VERSION 5.8 ;
BUSBITCHARS "[]" ;
DIVIDERCHAR "/" ;
UNITS
    DATABASE MICRONS 2000 ;
END UNITS

VIA PLL_COUNTER_DCO_PHYS_via1_2_2240_1200_1_2_1040_1040
  VIARULE Via1_GEN_HH ;
  CUTSIZE 0.26 0.26 ;
  LAYERS Metal1 Via1 Metal2 ;
  CUTSPACING 0.26 0.26 ;
  ENCLOSURE 0.06 0.17 0.01 0.06 ;
  ROWCOL 1 2 ;
END PLL_COUNTER_DCO_PHYS_via1_2_2240_1200_1_2_1040_1040

VIA PLL_COUNTER_DCO_PHYS_via2_3_2240_1200_1_2_1040_1040
  VIARULE Via2_GEN_HH ;
  CUTSIZE 0.26 0.26 ;
  LAYERS Metal2 Via2 Metal3 ;
  CUTSPACING 0.26 0.26 ;
  ENCLOSURE 0.01 0.06 0.06 0.01 ;
  ROWCOL 1 2 ;
END PLL_COUNTER_DCO_PHYS_via2_3_2240_1200_1_2_1040_1040

VIA PLL_COUNTER_DCO_PHYS_via3_4_2240_1200_1_2_1040_1040
  VIARULE Via3_GEN_HH ;
  CUTSIZE 0.26 0.26 ;
  LAYERS Metal3 Via3 Metal4 ;
  CUTSPACING 0.26 0.26 ;
  ENCLOSURE 0.06 0.01 0.17 0.06 ;
  ROWCOL 1 2 ;
END PLL_COUNTER_DCO_PHYS_via3_4_2240_1200_1_2_1040_1040

VIA PLL_COUNTER_DCO_PHYS_via4_5_2240_1800_2_2_1040_1040
  VIARULE Via4_GEN_HH ;
  CUTSIZE 0.26 0.26 ;
  LAYERS Metal4 Via4 Metal5 ;
  CUTSPACING 0.26 0.26 ;
  ENCLOSURE 0.17 0.06 0.06 0.06 ;
  ROWCOL 2 2 ;
END PLL_COUNTER_DCO_PHYS_via4_5_2240_1800_2_2_1040_1040

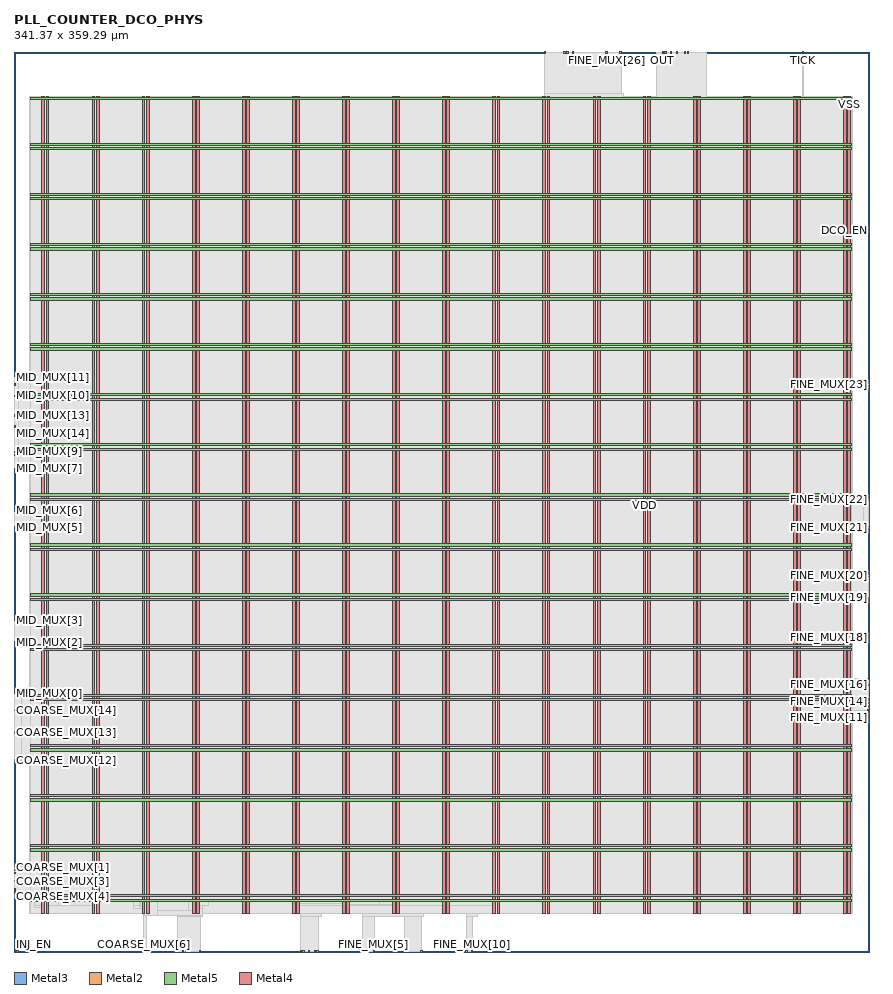
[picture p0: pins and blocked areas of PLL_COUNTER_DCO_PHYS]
MACRO PLL_COUNTER_DCO_PHYS
  FOREIGN PLL_COUNTER_DCO_PHYS 0 0 ;
  CLASS BLOCK ;
  SIZE 341.37 BY 359.29 ;
  PIN COARSE_MUX[0]
    DIRECTION INPUT ;
    USE SIGNAL ;
    PORT
      LAYER Metal3 ;
        RECT  0 32.48 0.56 33.04 ;
    END
  END COARSE_MUX[0]
  PIN COARSE_MUX[10]
    DIRECTION INPUT ;
    USE SIGNAL ;
    PORT
      LAYER Metal2 ;
        RECT  73.92 0 74.48 0.56 ;
    END
  END COARSE_MUX[10]
  PIN COARSE_MUX[11]
    DIRECTION INPUT ;
    USE SIGNAL ;
    PORT
      LAYER Metal2 ;
        RECT  64.96 0 65.52 0.56 ;
    END
  END COARSE_MUX[11]
  PIN COARSE_MUX[12]
    DIRECTION INPUT ;
    USE SIGNAL ;
    PORT
      LAYER Metal3 ;
        RECT  0 76.16 0.56 76.72 ;
    END
  END COARSE_MUX[12]
  PIN COARSE_MUX[13]
    DIRECTION INPUT ;
    USE SIGNAL ;
    PORT
      LAYER Metal3 ;
        RECT  0 87.36 0.56 87.92 ;
    END
  END COARSE_MUX[13]
  PIN COARSE_MUX[14]
    DIRECTION INPUT ;
    USE SIGNAL ;
    PORT
      LAYER Metal3 ;
        RECT  0 96.32 0.56 96.88 ;
    END
  END COARSE_MUX[14]
  PIN COARSE_MUX[1]
    DIRECTION INPUT ;
    USE SIGNAL ;
    PORT
      LAYER Metal3 ;
        RECT  0 33.6 0.56 34.16 ;
    END
  END COARSE_MUX[1]
  PIN COARSE_MUX[2]
    DIRECTION INPUT ;
    USE SIGNAL ;
    PORT
      LAYER Metal3 ;
        RECT  0 31.36 0.56 31.92 ;
    END
  END COARSE_MUX[2]
  PIN COARSE_MUX[3]
    DIRECTION INPUT ;
    USE SIGNAL ;
    PORT
      LAYER Metal3 ;
        RECT  0 28 0.56 28.56 ;
    END
  END COARSE_MUX[3]
  PIN COARSE_MUX[4]
    DIRECTION INPUT ;
    USE SIGNAL ;
    PORT
      LAYER Metal3 ;
        RECT  0 24.64 0.56 25.2 ;
    END
  END COARSE_MUX[4]
  PIN COARSE_MUX[5]
    DIRECTION INPUT ;
    USE SIGNAL ;
    PORT
      LAYER Metal3 ;
        RECT  0 23.52 0.56 24.08 ;
    END
  END COARSE_MUX[5]
  PIN COARSE_MUX[6]
    DIRECTION INPUT ;
    USE SIGNAL ;
    PORT
      LAYER Metal2 ;
        RECT  51.52 0 52.08 0.56 ;
    END
  END COARSE_MUX[6]
  PIN COARSE_MUX[7]
    DIRECTION INPUT ;
    USE SIGNAL ;
    PORT
      LAYER Metal2 ;
        RECT  52.64 0 53.2 0.56 ;
    END
  END COARSE_MUX[7]
  PIN COARSE_MUX[8]
    DIRECTION INPUT ;
    USE SIGNAL ;
    PORT
      LAYER Metal2 ;
        RECT  67.2 0 67.76 0.56 ;
    END
  END COARSE_MUX[8]
  PIN COARSE_MUX[9]
    DIRECTION INPUT ;
    USE SIGNAL ;
    PORT
      LAYER Metal2 ;
        RECT  68.32 0 68.88 0.56 ;
    END
  END COARSE_MUX[9]
  PIN DCO_EN
    DIRECTION INPUT ;
    USE SIGNAL ;
    PORT
      LAYER Metal3 ;
        RECT  340.81 287.84 341.37 288.4 ;
    END
  END DCO_EN
  PIN FINE_MUX[0]
    DIRECTION INPUT ;
    USE SIGNAL ;
    PORT
      LAYER Metal2 ;
        RECT  114.24 0 114.8 0.56 ;
    END
  END FINE_MUX[0]
  PIN FINE_MUX[10]
    DIRECTION INPUT ;
    USE SIGNAL ;
    PORT
      LAYER Metal2 ;
        RECT  182.56 0 183.12 0.56 ;
    END
  END FINE_MUX[10]
  PIN FINE_MUX[11]
    DIRECTION INPUT ;
    USE SIGNAL ;
    PORT
      LAYER Metal3 ;
        RECT  340.81 96.32 341.37 96.88 ;
    END
  END FINE_MUX[11]
  PIN FINE_MUX[12]
    DIRECTION INPUT ;
    USE SIGNAL ;
    PORT
      LAYER Metal3 ;
        RECT  340.81 97.44 341.37 98 ;
    END
  END FINE_MUX[12]
  PIN FINE_MUX[13]
    DIRECTION INPUT ;
    USE SIGNAL ;
    PORT
      LAYER Metal3 ;
        RECT  340.81 98.56 341.37 99.12 ;
    END
  END FINE_MUX[13]
  PIN FINE_MUX[14]
    DIRECTION INPUT ;
    USE SIGNAL ;
    PORT
      LAYER Metal3 ;
        RECT  340.81 99.68 341.37 100.24 ;
    END
  END FINE_MUX[14]
  PIN FINE_MUX[15]
    DIRECTION INPUT ;
    USE SIGNAL ;
    PORT
      LAYER Metal3 ;
        RECT  340.81 100.8 341.37 101.36 ;
    END
  END FINE_MUX[15]
  PIN FINE_MUX[16]
    DIRECTION INPUT ;
    USE SIGNAL ;
    PORT
      LAYER Metal3 ;
        RECT  340.81 106.4 341.37 106.96 ;
    END
  END FINE_MUX[16]
  PIN FINE_MUX[17]
    DIRECTION INPUT ;
    USE SIGNAL ;
    PORT
      LAYER Metal3 ;
        RECT  340.81 108.64 341.37 109.2 ;
    END
  END FINE_MUX[17]
  PIN FINE_MUX[18]
    DIRECTION INPUT ;
    USE SIGNAL ;
    PORT
      LAYER Metal3 ;
        RECT  340.81 125.44 341.37 126 ;
    END
  END FINE_MUX[18]
  PIN FINE_MUX[19]
    DIRECTION INPUT ;
    USE SIGNAL ;
    PORT
      LAYER Metal3 ;
        RECT  340.81 141.12 341.37 141.68 ;
    END
  END FINE_MUX[19]
  PIN FINE_MUX[1]
    DIRECTION INPUT ;
    USE SIGNAL ;
    PORT
      LAYER Metal2 ;
        RECT  115.36 0 115.92 0.56 ;
    END
  END FINE_MUX[1]
  PIN FINE_MUX[20]
    DIRECTION INPUT ;
    USE SIGNAL ;
    PORT
      LAYER Metal3 ;
        RECT  340.81 150.08 341.37 150.64 ;
    END
  END FINE_MUX[20]
  PIN FINE_MUX[21]
    DIRECTION INPUT ;
    USE SIGNAL ;
    PORT
      LAYER Metal3 ;
        RECT  340.81 169.12 341.37 169.68 ;
    END
  END FINE_MUX[21]
  PIN FINE_MUX[22]
    DIRECTION INPUT ;
    USE SIGNAL ;
    PORT
      LAYER Metal3 ;
        RECT  340.81 180.32 341.37 180.88 ;
    END
  END FINE_MUX[22]
  PIN FINE_MUX[23]
    DIRECTION INPUT ;
    USE SIGNAL ;
    PORT
      LAYER Metal3 ;
        RECT  340.81 226.24 341.37 226.8 ;
    END
  END FINE_MUX[23]
  PIN FINE_MUX[24]
    DIRECTION INPUT ;
    USE SIGNAL ;
    PORT
      LAYER Metal3 ;
        RECT  340.81 225.12 341.37 225.68 ;
    END
  END FINE_MUX[24]
  PIN FINE_MUX[25]
    DIRECTION INPUT ;
    USE SIGNAL ;
    PORT
      LAYER Metal2 ;
        RECT  241.92 358.73 242.48 359.29 ;
    END
  END FINE_MUX[25]
  PIN FINE_MUX[26]
    DIRECTION INPUT ;
    USE SIGNAL ;
    PORT
      LAYER Metal2 ;
        RECT  236.32 358.73 236.88 359.29 ;
    END
  END FINE_MUX[26]
  PIN FINE_MUX[27]
    DIRECTION INPUT ;
    USE SIGNAL ;
    PORT
      LAYER Metal2 ;
        RECT  219.52 358.73 220.08 359.29 ;
    END
  END FINE_MUX[27]
  PIN FINE_MUX[28]
    DIRECTION INPUT ;
    USE SIGNAL ;
    PORT
      LAYER Metal2 ;
        RECT  222.88 358.73 223.44 359.29 ;
    END
  END FINE_MUX[28]
  PIN FINE_MUX[29]
    DIRECTION INPUT ;
    USE SIGNAL ;
    PORT
      LAYER Metal2 ;
        RECT  211.68 358.73 212.24 359.29 ;
    END
  END FINE_MUX[29]
  PIN FINE_MUX[2]
    DIRECTION INPUT ;
    USE SIGNAL ;
    PORT
      LAYER Metal2 ;
        RECT  117.6 0 118.16 0.56 ;
    END
  END FINE_MUX[2]
  PIN FINE_MUX[30]
    DIRECTION INPUT ;
    USE SIGNAL ;
    PORT
      LAYER Metal2 ;
        RECT  220.64 358.73 221.2 359.29 ;
    END
  END FINE_MUX[30]
  PIN FINE_MUX[3]
    DIRECTION INPUT ;
    USE SIGNAL ;
    PORT
      LAYER Metal2 ;
        RECT  120.96 0 121.52 0.56 ;
    END
  END FINE_MUX[3]
  PIN FINE_MUX[4]
    DIRECTION INPUT ;
    USE SIGNAL ;
    PORT
      LAYER Metal2 ;
        RECT  119.84 0 120.4 0.56 ;
    END
  END FINE_MUX[4]
  PIN FINE_MUX[5]
    DIRECTION INPUT ;
    USE SIGNAL ;
    PORT
      LAYER Metal2 ;
        RECT  143.36 0 143.92 0.56 ;
    END
  END FINE_MUX[5]
  PIN FINE_MUX[6]
    DIRECTION INPUT ;
    USE SIGNAL ;
    PORT
      LAYER Metal2 ;
        RECT  138.88 0 139.44 0.56 ;
    END
  END FINE_MUX[6]
  PIN FINE_MUX[7]
    DIRECTION INPUT ;
    USE SIGNAL ;
    PORT
      LAYER Metal2 ;
        RECT  155.68 0 156.24 0.56 ;
    END
  END FINE_MUX[7]
  PIN FINE_MUX[8]
    DIRECTION INPUT ;
    USE SIGNAL ;
    PORT
      LAYER Metal2 ;
        RECT  162.4 0 162.96 0.56 ;
    END
  END FINE_MUX[8]
  PIN FINE_MUX[9]
    DIRECTION INPUT ;
    USE SIGNAL ;
    PORT
      LAYER Metal2 ;
        RECT  180.32 0 180.88 0.56 ;
    END
  END FINE_MUX[9]
  PIN INJ_EDGE
    DIRECTION OUTPUT ;
    USE SIGNAL ;
    PORT
      LAYER Metal2 ;
        RECT  264.32 358.73 264.88 359.29 ;
    END
  END INJ_EDGE
  PIN INJ_EN
    DIRECTION INPUT ;
    USE SIGNAL ;
    PORT
      LAYER Metal2 ;
        RECT  1.12 0 1.68 0.56 ;
    END
  END INJ_EN
  PIN MID_MUX[0]
    DIRECTION INPUT ;
    USE SIGNAL ;
    PORT
      LAYER Metal3 ;
        RECT  0 103.04 0.56 103.6 ;
    END
  END MID_MUX[0]
  PIN MID_MUX[10]
    DIRECTION INPUT ;
    USE SIGNAL ;
    PORT
      LAYER Metal3 ;
        RECT  0 221.76 0.56 222.32 ;
    END
  END MID_MUX[10]
  PIN MID_MUX[11]
    DIRECTION INPUT ;
    USE SIGNAL ;
    PORT
      LAYER Metal3 ;
        RECT  0 226.24 0.56 226.8 ;
    END
  END MID_MUX[11]
  PIN MID_MUX[12]
    DIRECTION INPUT ;
    USE SIGNAL ;
    PORT
      LAYER Metal3 ;
        RECT  0 229.6 0.56 230.16 ;
    END
  END MID_MUX[12]
  PIN MID_MUX[13]
    DIRECTION INPUT ;
    USE SIGNAL ;
    PORT
      LAYER Metal3 ;
        RECT  0 213.92 0.56 214.48 ;
    END
  END MID_MUX[13]
  PIN MID_MUX[14]
    DIRECTION INPUT ;
    USE SIGNAL ;
    PORT
      LAYER Metal3 ;
        RECT  0 209.44 0.56 210 ;
    END
  END MID_MUX[14]
  PIN MID_MUX[1]
    DIRECTION INPUT ;
    USE SIGNAL ;
    PORT
      LAYER Metal3 ;
        RECT  0 104.16 0.56 104.72 ;
    END
  END MID_MUX[1]
  PIN MID_MUX[2]
    DIRECTION INPUT ;
    USE SIGNAL ;
    PORT
      LAYER Metal3 ;
        RECT  0 123.2 0.56 123.76 ;
    END
  END MID_MUX[2]
  PIN MID_MUX[3]
    DIRECTION INPUT ;
    USE SIGNAL ;
    PORT
      LAYER Metal3 ;
        RECT  0 132.16 0.56 132.72 ;
    END
  END MID_MUX[3]
  PIN MID_MUX[4]
    DIRECTION INPUT ;
    USE SIGNAL ;
    PORT
      LAYER Metal3 ;
        RECT  0 133.28 0.56 133.84 ;
    END
  END MID_MUX[4]
  PIN MID_MUX[5]
    DIRECTION INPUT ;
    USE SIGNAL ;
    PORT
      LAYER Metal3 ;
        RECT  0 169.12 0.56 169.68 ;
    END
  END MID_MUX[5]
  PIN MID_MUX[6]
    DIRECTION INPUT ;
    USE SIGNAL ;
    PORT
      LAYER Metal3 ;
        RECT  0 175.84 0.56 176.4 ;
    END
  END MID_MUX[6]
  PIN MID_MUX[7]
    DIRECTION INPUT ;
    USE SIGNAL ;
    PORT
      LAYER Metal3 ;
        RECT  0 192.64 0.56 193.2 ;
    END
  END MID_MUX[7]
  PIN MID_MUX[8]
    DIRECTION INPUT ;
    USE SIGNAL ;
    PORT
      LAYER Metal3 ;
        RECT  0 198.24 0.56 198.8 ;
    END
  END MID_MUX[8]
  PIN MID_MUX[9]
    DIRECTION INPUT ;
    USE SIGNAL ;
    PORT
      LAYER Metal3 ;
        RECT  0 199.36 0.56 199.92 ;
    END
  END MID_MUX[9]
  PIN MID_OUT
    DIRECTION OUTPUT ;
    USE SIGNAL ;
    PORT
      LAYER Metal2 ;
        RECT  259.84 358.73 260.4 359.29 ;
    END
  END MID_OUT
  PIN OUT
    DIRECTION OUTPUT ;
    USE SIGNAL ;
    PORT
      LAYER Metal2 ;
        RECT  258.72 358.73 259.28 359.29 ;
    END
  END OUT
  PIN REF
    DIRECTION INPUT ;
    USE SIGNAL ;
    PORT
      LAYER Metal2 ;
        RECT  262.08 358.73 262.64 359.29 ;
    END
  END REF
  PIN SS_BBPD[0]
    DIRECTION OUTPUT ;
    USE SIGNAL ;
    PORT
      LAYER Metal2 ;
        RECT  267.68 358.73 268.24 359.29 ;
    END
  END SS_BBPD[0]
  PIN SS_BBPD[1]
    DIRECTION OUTPUT ;
    USE SIGNAL ;
    PORT
      LAYER Metal2 ;
        RECT  268.8 358.73 269.36 359.29 ;
    END
  END SS_BBPD[1]
  PIN TICK
    DIRECTION INPUT ;
    USE SIGNAL ;
    PORT
      LAYER Metal2 ;
        RECT  314.72 358.73 315.28 359.29 ;
    END
  END TICK
  PIN VDD
    DIRECTION INOUT ;
    USE POWER ;
    PORT
      LAYER Metal5 ;
        RECT  6.72 340.23 334.32 341.13 ;
        RECT  6.72 320.23 334.32 321.13 ;
        RECT  6.72 300.23 334.32 301.13 ;
        RECT  6.72 280.23 334.32 281.13 ;
        RECT  6.72 260.23 334.32 261.13 ;
        RECT  6.72 240.23 334.32 241.13 ;
        RECT  6.72 220.23 334.32 221.13 ;
        RECT  6.72 200.23 334.32 201.13 ;
        RECT  6.72 180.23 334.32 181.13 ;
        RECT  6.72 160.23 334.32 161.13 ;
        RECT  6.72 140.23 334.32 141.13 ;
        RECT  6.72 120.23 334.32 121.13 ;
        RECT  6.72 100.23 334.32 101.13 ;
        RECT  6.72 80.23 334.32 81.13 ;
        RECT  6.72 60.23 334.32 61.13 ;
        RECT  6.72 40.23 334.32 41.13 ;
        RECT  6.72 20.23 334.32 21.13 ;
      LAYER Metal4 ;
        RECT  331.16 15.38 332.28 341.34 ;
        RECT  311.16 15.38 312.28 341.34 ;
        RECT  291.16 15.38 292.28 341.34 ;
        RECT  271.16 15.38 272.28 341.34 ;
        RECT  251.16 15.38 252.28 341.34 ;
        RECT  231.16 15.38 232.28 341.34 ;
        RECT  211.16 15.38 212.28 341.34 ;
        RECT  191.16 15.38 192.28 341.34 ;
        RECT  171.16 15.38 172.28 341.34 ;
        RECT  151.16 15.38 152.28 341.34 ;
        RECT  131.16 15.38 132.28 341.34 ;
        RECT  111.16 15.38 112.28 341.34 ;
        RECT  91.16 15.38 92.28 341.34 ;
        RECT  71.16 15.38 72.28 341.34 ;
        RECT  51.16 15.38 52.28 341.34 ;
        RECT  31.16 15.38 32.28 341.34 ;
        RECT  11.16 15.38 12.28 341.34 ;
    END
  END VDD
  PIN VSS
    DIRECTION INOUT ;
    USE GROUND ;
    PORT
      LAYER Metal5 ;
        RECT  6.72 322.03 334.32 322.93 ;
        RECT  6.72 302.03 334.32 302.93 ;
        RECT  6.72 282.03 334.32 282.93 ;
        RECT  6.72 262.03 334.32 262.93 ;
        RECT  6.72 242.03 334.32 242.93 ;
        RECT  6.72 222.03 334.32 222.93 ;
        RECT  6.72 202.03 334.32 202.93 ;
        RECT  6.72 182.03 334.32 182.93 ;
        RECT  6.72 162.03 334.32 162.93 ;
        RECT  6.72 142.03 334.32 142.93 ;
        RECT  6.72 122.03 334.32 122.93 ;
        RECT  6.72 102.03 334.32 102.93 ;
        RECT  6.72 82.03 334.32 82.93 ;
        RECT  6.72 62.03 334.32 62.93 ;
        RECT  6.72 42.03 334.32 42.93 ;
        RECT  6.72 22.03 334.32 22.93 ;
      LAYER Metal4 ;
        RECT  332.84 15.38 333.96 341.34 ;
        RECT  312.84 15.38 313.96 341.34 ;
        RECT  292.84 15.38 293.96 341.34 ;
        RECT  272.84 15.38 273.96 341.34 ;
        RECT  252.84 15.38 253.96 341.34 ;
        RECT  232.84 15.38 233.96 341.34 ;
        RECT  212.84 15.38 213.96 341.34 ;
        RECT  192.84 15.38 193.96 341.34 ;
        RECT  172.84 15.38 173.96 341.34 ;
        RECT  152.84 15.38 153.96 341.34 ;
        RECT  132.84 15.38 133.96 341.34 ;
        RECT  112.84 15.38 113.96 341.34 ;
        RECT  92.84 15.38 93.96 341.34 ;
        RECT  72.84 15.38 73.96 341.34 ;
        RECT  52.84 15.38 53.96 341.34 ;
        RECT  32.84 15.38 33.96 341.34 ;
        RECT  12.84 15.38 13.96 341.34 ;
    END
  END VSS
  OBS
    LAYER Pwell ;
     RECT  6.29 15.25 334.75 17.45 ;
     RECT  6.29 21.75 334.75 25.29 ;
     RECT  6.29 29.59 334.75 33.13 ;
     RECT  6.29 37.43 334.75 40.97 ;
     RECT  6.29 45.27 334.75 48.81 ;
     RECT  6.29 53.11 334.75 56.65 ;
     RECT  6.29 60.95 334.75 64.49 ;
     RECT  6.29 68.79 334.75 72.33 ;
     RECT  6.29 76.63 334.75 80.17 ;
     RECT  6.29 84.47 334.75 88.01 ;
     RECT  6.29 92.31 334.75 95.85 ;
     RECT  6.29 100.15 334.75 103.69 ;
     RECT  6.29 107.99 334.75 111.53 ;
     RECT  6.29 115.83 334.75 119.37 ;
     RECT  6.29 123.67 334.75 127.21 ;
     RECT  6.29 131.51 334.75 135.05 ;
     RECT  6.29 139.35 334.75 142.89 ;
     RECT  6.29 147.19 334.75 150.73 ;
     RECT  6.29 155.03 334.75 158.57 ;
     RECT  6.29 162.87 334.75 166.41 ;
     RECT  6.29 170.71 334.75 174.25 ;
     RECT  6.29 178.55 334.75 182.09 ;
     RECT  6.29 186.39 334.75 189.93 ;
     RECT  6.29 194.23 334.75 197.77 ;
     RECT  6.29 202.07 334.75 205.61 ;
     RECT  6.29 209.91 334.75 213.45 ;
     RECT  6.29 217.75 334.75 221.29 ;
     RECT  6.29 225.59 334.75 229.13 ;
     RECT  6.29 233.43 334.75 236.97 ;
     RECT  6.29 241.27 334.75 244.81 ;
     RECT  6.29 249.11 334.75 252.65 ;
     RECT  6.29 256.95 334.75 260.49 ;
     RECT  6.29 264.79 334.75 268.33 ;
     RECT  6.29 272.63 334.75 276.17 ;
     RECT  6.29 280.47 334.75 284.01 ;
     RECT  6.29 288.31 334.75 291.85 ;
     RECT  6.29 296.15 334.75 299.69 ;
     RECT  6.29 303.99 334.75 307.53 ;
     RECT  6.29 311.83 334.75 315.37 ;
     RECT  6.29 319.67 334.75 323.21 ;
     RECT  6.29 327.51 334.75 331.05 ;
     RECT  6.29 335.35 334.75 338.89 ;
    LAYER Nwell ;
     RECT  6.29 17.45 334.75 21.75 ;
     RECT  6.29 25.29 334.75 29.59 ;
     RECT  6.29 33.13 334.75 37.43 ;
     RECT  6.29 40.97 334.75 45.27 ;
     RECT  6.29 48.81 334.75 53.11 ;
     RECT  6.29 56.65 334.75 60.95 ;
     RECT  6.29 64.49 334.75 68.79 ;
     RECT  6.29 72.33 334.75 76.63 ;
     RECT  6.29 80.17 334.75 84.47 ;
     RECT  6.29 88.01 334.75 92.31 ;
     RECT  6.29 95.85 334.75 100.15 ;
     RECT  6.29 103.69 334.75 107.99 ;
     RECT  6.29 111.53 334.75 115.83 ;
     RECT  6.29 119.37 334.75 123.67 ;
     RECT  6.29 127.21 334.75 131.51 ;
     RECT  6.29 135.05 334.75 139.35 ;
     RECT  6.29 142.89 334.75 147.19 ;
     RECT  6.29 150.73 334.75 155.03 ;
     RECT  6.29 158.57 334.75 162.87 ;
     RECT  6.29 166.41 334.75 170.71 ;
     RECT  6.29 174.25 334.75 178.55 ;
     RECT  6.29 182.09 334.75 186.39 ;
     RECT  6.29 189.93 334.75 194.23 ;
     RECT  6.29 197.77 334.75 202.07 ;
     RECT  6.29 205.61 334.75 209.91 ;
     RECT  6.29 213.45 334.75 217.75 ;
     RECT  6.29 221.29 334.75 225.59 ;
     RECT  6.29 229.13 334.75 233.43 ;
     RECT  6.29 236.97 334.75 241.27 ;
     RECT  6.29 244.81 334.75 249.11 ;
     RECT  6.29 252.65 334.75 256.95 ;
     RECT  6.29 260.49 334.75 264.79 ;
     RECT  6.29 268.33 334.75 272.63 ;
     RECT  6.29 276.17 334.75 280.47 ;
     RECT  6.29 284.01 334.75 288.31 ;
     RECT  6.29 291.85 334.75 296.15 ;
     RECT  6.29 299.69 334.75 303.99 ;
     RECT  6.29 307.53 334.75 311.83 ;
     RECT  6.29 315.37 334.75 319.67 ;
     RECT  6.29 323.21 334.75 327.51 ;
     RECT  6.29 331.05 334.75 335.35 ;
     RECT  6.29 338.89 334.75 341.47 ;
    LAYER Metal1 ;
     RECT  6.72 15.38 334.32 341.34 ;
    LAYER Metal2 ;
     RECT  65.1 0.28 74.34 14.14 ;
     RECT  114.38 0.28 121.38 14.14 ;
     RECT  139.02 0.28 143.78 14.14 ;
     RECT  155.82 0.28 162.82 14.14 ;
     RECT  180.46 0.28 182.98 14.14 ;
     RECT  51.66 0.28 53.06 14.7 ;
     RECT  65.1 14.14 75.18 14.7 ;
     RECT  114.38 14.14 122.78 15.49 ;
     RECT  139.02 14.14 163.66 15.49 ;
     RECT  180.46 14.14 184.94 15.49 ;
     RECT  51.66 14.7 75.18 17.305 ;
     RECT  48.86 17.305 75.18 17.35 ;
     RECT  13 15.49 13.8 17.78 ;
     RECT  8.26 17.78 13.8 18.62 ;
     RECT  33 15.49 33.8 18.62 ;
     RECT  47.74 17.35 75.18 18.62 ;
     RECT  113 15.49 193.8 18.76 ;
     RECT  93 15.49 93.8 19.41 ;
     RECT  113 18.76 133.8 19.41 ;
     RECT  213 15.49 213.8 19.41 ;
     RECT  233 15.49 233.8 19.41 ;
     RECT  253 15.49 253.8 19.41 ;
     RECT  273 15.49 273.8 19.41 ;
     RECT  293 15.49 293.8 19.41 ;
     RECT  313 15.49 313.8 19.41 ;
     RECT  333 15.49 333.8 19.41 ;
     RECT  8.26 18.62 33.8 20.86 ;
     RECT  47.74 18.62 77.7 21.42 ;
     RECT  47.18 21.42 77.7 25.15 ;
     RECT  6.3 20.86 33.8 25.34 ;
     RECT  46.62 25.15 77.7 25.34 ;
     RECT  6.3 25.34 77.7 25.9 ;
     RECT  0.7 25.9 77.7 28.42 ;
     RECT  6.86 28.42 77.7 31.78 ;
     RECT  7.42 31.78 77.7 33.46 ;
     RECT  31.32 33.46 77.7 34.86 ;
     RECT  91.32 19.41 93.8 34.86 ;
     RECT  111.32 19.41 133.8 35.98 ;
     RECT  7.42 33.46 17.78 37.94 ;
     RECT  106.54 35.98 133.8 40.46 ;
     RECT  145.74 18.76 193.8 40.46 ;
     RECT  106.54 40.46 193.8 40.74 ;
     RECT  8.26 37.94 17.78 41.02 ;
     RECT  106.26 40.74 193.8 41.3 ;
     RECT  31.32 34.86 93.8 48.3 ;
     RECT  11.32 41.02 17.78 48.86 ;
     RECT  29.915 48.3 93.8 48.86 ;
     RECT  106.54 41.3 193.8 49.98 ;
     RECT  211.32 19.41 213.8 49.98 ;
     RECT  106.54 49.98 213.8 53.34 ;
     RECT  11.32 48.86 93.8 56.7 ;
     RECT  106.54 53.34 218.82 56.7 ;
     RECT  11.32 56.7 218.82 59.64 ;
     RECT  11.06 59.64 218.82 61.18 ;
     RECT  251.32 19.41 253.8 64.26 ;
     RECT  9.66 61.18 218.82 65.975 ;
     RECT  169.82 65.975 218.82 67.305 ;
     RECT  231.32 19.41 233.8 67.305 ;
     RECT  246.26 64.26 253.8 67.305 ;
     RECT  169.82 67.305 257.39 68.53 ;
     RECT  9.66 65.975 157.78 68.74 ;
     RECT  169.82 68.53 257.395 68.74 ;
     RECT  169.82 68.74 259.04 69.02 ;
     RECT  271.32 19.41 273.8 69.02 ;
     RECT  169.82 69.02 273.8 71.425 ;
     RECT  9.66 68.74 154.98 72.38 ;
     RECT  169.82 71.425 278.13 72.38 ;
     RECT  169.82 72.38 279.76 72.66 ;
     RECT  206.22 72.66 279.76 73.5 ;
     RECT  291.32 19.41 293.8 73.5 ;
     RECT  9.66 72.38 39.06 76.3 ;
     RECT  206.22 73.5 293.8 76.3 ;
     RECT  311.32 19.41 313.8 76.3 ;
     RECT  51.32 72.38 154.98 80.025 ;
     RECT  169.82 72.66 193.8 80.025 ;
     RECT  206.22 76.3 313.8 83.95 ;
     RECT  51.32 80.025 193.8 84.14 ;
     RECT  205.1 83.95 313.8 84.14 ;
     RECT  8.54 76.3 39.06 84.42 ;
     RECT  8.26 84.42 39.06 87.87 ;
     RECT  51.32 84.14 313.8 87.87 ;
     RECT  331.32 19.41 333.8 88.62 ;
     RECT  8.26 87.87 313.8 89.46 ;
     RECT  8.26 89.46 154.98 92.12 ;
     RECT  166.46 89.46 313.8 102.785 ;
     RECT  327.74 88.62 333.8 102.785 ;
     RECT  166.46 102.785 333.8 103.18 ;
     RECT  8.26 92.12 154.42 103.62 ;
     RECT  165.9 103.18 333.8 103.62 ;
     RECT  8.26 103.62 333.8 107.66 ;
     RECT  11.32 107.66 333.8 123.15 ;
     RECT  8.26 123.15 333.8 125.58 ;
     RECT  8.26 125.58 334.74 126.42 ;
     RECT  8.26 126.42 333.8 132.3 ;
     RECT  7.42 132.3 333.8 135.94 ;
     RECT  8.26 135.94 333.8 139.02 ;
     RECT  9.1 139.02 333.8 139.86 ;
     RECT  10.755 139.86 333.8 143.725 ;
     RECT  10.81 143.725 333.8 144.375 ;
     RECT  11.32 144.375 333.8 158.62 ;
     RECT  10.22 158.62 333.8 165.62 ;
     RECT  187.18 165.62 333.8 166.18 ;
     RECT  10.22 165.62 157.22 166.46 ;
     RECT  9.66 166.46 157.22 166.74 ;
     RECT  191.1 166.18 333.8 166.74 ;
     RECT  9.66 166.74 156.38 167.3 ;
     RECT  170.38 165.62 173.8 167.3 ;
     RECT  9.66 167.3 153.8 167.895 ;
     RECT  191.32 166.74 333.8 167.895 ;
     RECT  9.66 167.895 135.94 168.42 ;
     RECT  209.86 167.895 333.8 169.54 ;
     RECT  9.66 168.42 135.38 169.82 ;
     RECT  9.66 169.82 134.82 170.38 ;
     RECT  211.32 169.54 333.8 170.66 ;
     RECT  211.32 170.66 319.62 170.845 ;
     RECT  9.38 170.38 134.82 173.46 ;
     RECT  9.38 173.46 134.26 174.58 ;
     RECT  227.5 170.845 319.62 175.7 ;
     RECT  8.26 174.58 134.26 176.26 ;
     RECT  9.66 176.26 134.26 177.38 ;
     RECT  9.66 177.38 133.8 178.5 ;
     RECT  231.32 175.7 319.62 182.14 ;
     RECT  331.1 170.66 333.8 182.14 ;
     RECT  11.32 178.5 133.8 183.575 ;
     RECT  11.32 183.575 116.9 186.9 ;
     RECT  11.32 186.9 113.8 189.98 ;
     RECT  9.66 189.98 113.8 190.26 ;
     RECT  8.26 190.26 113.8 199.5 ;
     RECT  7.42 199.5 113.8 210.42 ;
     RECT  211.32 170.845 213.8 216.3 ;
     RECT  231.32 182.14 333.8 216.3 ;
     RECT  8.26 210.42 113.8 217.7 ;
     RECT  25.9 217.7 113.8 218.26 ;
     RECT  28.845 218.26 113.8 218.61 ;
     RECT  30.29 218.61 113.8 218.655 ;
     RECT  211.32 216.3 333.8 221.34 ;
     RECT  305.965 221.34 333.8 221.55 ;
     RECT  305.97 221.55 333.8 222.775 ;
     RECT  311.32 222.775 333.8 224.42 ;
     RECT  211.32 221.34 293.8 224.7 ;
     RECT  30.38 218.655 113.8 225.54 ;
     RECT  327.74 224.42 333.8 228.34 ;
     RECT  31.32 225.54 113.8 229.18 ;
     RECT  209.58 224.7 293.8 229.18 ;
     RECT  329.14 228.34 333.8 229.18 ;
     RECT  209.02 229.18 293.8 230.23 ;
     RECT  51.32 229.18 113.8 230.58 ;
     RECT  51.32 230.58 73.8 232.26 ;
     RECT  8.26 217.7 13.8 233.1 ;
     RECT  66.78 232.26 73.8 233.38 ;
     RECT  67.34 233.38 73.8 234.5 ;
     RECT  208.695 230.23 293.8 235.34 ;
     RECT  206.875 235.34 293.8 236.83 ;
     RECT  206.875 236.83 293.86 237.58 ;
     RECT  206.875 237.58 296.1 238.14 ;
     RECT  205.1 238.14 296.1 239.82 ;
     RECT  311.32 224.42 313.8 239.82 ;
     RECT  205.1 239.82 313.8 240.1 ;
     RECT  191.32 167.895 193.8 244.67 ;
     RECT  205.1 240.1 300.02 244.67 ;
     RECT  191.32 244.67 300.02 251.86 ;
     RECT  311.32 240.1 313.8 251.86 ;
     RECT  331.32 229.18 333.8 272.3 ;
     RECT  330.54 272.3 333.8 283.095 ;
     RECT  191.32 251.86 313.8 283.295 ;
     RECT  328.86 283.095 333.8 283.295 ;
     RECT  191.32 283.295 333.8 303.66 ;
     RECT  189.42 303.66 333.8 316.5 ;
     RECT  189.42 316.5 315.14 319.62 ;
     RECT  326.62 316.5 333.8 324.1 ;
     RECT  189.42 319.62 314.58 331.38 ;
     RECT  191.32 331.38 314.58 331.81 ;
     RECT  288.275 331.81 314.58 332.18 ;
     RECT  289.1 332.18 314.58 334.18 ;
     RECT  291.32 334.18 314.58 335.3 ;
     RECT  191.32 331.81 276.5 335.86 ;
     RECT  311.32 335.3 314.58 335.86 ;
     RECT  210.14 335.86 276.5 336.14 ;
     RECT  291.32 335.3 298.9 336.14 ;
     RECT  11.32 233.1 13.8 337.31 ;
     RECT  31.32 229.18 33.8 337.31 ;
     RECT  51.32 232.26 53.8 337.31 ;
     RECT  71.32 234.5 73.8 337.31 ;
     RECT  91.32 230.58 93.8 337.31 ;
     RECT  111.32 230.58 113.8 337.31 ;
     RECT  131.32 183.575 133.8 337.31 ;
     RECT  151.32 167.895 153.8 337.31 ;
     RECT  171.32 167.3 173.8 337.31 ;
     RECT  191.32 335.86 193.8 337.31 ;
     RECT  291.32 336.14 293.8 337.31 ;
     RECT  331.32 324.1 333.8 337.31 ;
     RECT  210.7 336.14 276.5 338.1 ;
     RECT  11.32 337.31 12.12 341.23 ;
     RECT  31.32 337.31 32.12 341.23 ;
     RECT  51.32 337.31 52.12 341.23 ;
     RECT  71.32 337.31 72.12 341.23 ;
     RECT  91.32 337.31 92.12 341.23 ;
     RECT  111.32 337.31 112.12 341.23 ;
     RECT  131.32 337.31 132.12 341.23 ;
     RECT  151.32 337.31 152.12 341.23 ;
     RECT  171.32 337.31 172.12 341.23 ;
     RECT  191.32 337.31 192.12 341.23 ;
     RECT  211.32 338.1 276.5 341.23 ;
     RECT  291.32 337.31 292.12 341.23 ;
     RECT  311.32 335.86 315.14 341.23 ;
     RECT  331.32 337.31 332.12 341.23 ;
     RECT  211.82 341.23 243.18 342.58 ;
     RECT  211.82 342.58 242.34 359.01 ;
     RECT  256.62 341.23 276.5 359.01 ;
     RECT  314.86 341.23 315.14 359.01 ;
     RECT  224.14 359.01 226.66 359.15 ;
     RECT  256.62 359.01 258.02 359.15 ;
     RECT  270.06 359.01 276.5 359.15 ;
    LAYER Metal3 ;
     RECT  0.28 192.78 1.82 230.02 ;
     RECT  0.28 76.3 2.94 104.58 ;
     RECT  0.28 23.66 9.1 34.02 ;
     RECT  0.28 123.34 9.1 133.7 ;
     RECT  9.1 21.42 9.66 34.02 ;
     RECT  2.94 76.3 9.66 105.14 ;
     RECT  1.82 192.78 9.66 230.58 ;
     RECT  0.28 169.26 10.22 176.26 ;
     RECT  9.66 61.18 11.06 61.46 ;
     RECT  9.66 21.42 11.27 37.94 ;
     RECT  11.06 59.5 11.27 61.46 ;
     RECT  9.66 76.3 11.27 106.82 ;
     RECT  9.1 123.34 11.27 139.86 ;
     RECT  10.22 158.62 11.27 176.26 ;
     RECT  9.66 189.98 11.27 232.26 ;
     RECT  11.27 19.46 12.17 341.18 ;
     RECT  12.17 19.46 12.95 337.26 ;
     RECT  12.95 15.54 13.85 337.26 ;
     RECT  13.85 18.62 17.78 174.58 ;
     RECT  13.85 187.74 25.9 232.26 ;
     RECT  17.78 48.3 27.02 174.58 ;
     RECT  25.9 186.06 27.02 232.26 ;
     RECT  17.78 18.62 31.27 33.46 ;
     RECT  27.02 48.3 31.27 232.26 ;
     RECT  31.27 18.62 32.17 341.18 ;
     RECT  32.17 18.62 32.95 337.26 ;
     RECT  32.95 15.54 33.85 337.26 ;
     RECT  33.85 22.54 35.14 139.86 ;
     RECT  35.14 22.54 35.7 139.3 ;
     RECT  35.7 22.54 36.82 72.66 ;
     RECT  33.85 154.14 45.5 168.98 ;
     RECT  33.85 185.5 45.5 232.26 ;
     RECT  36.82 22.54 47.18 71.54 ;
     RECT  47.18 21.98 47.74 71.54 ;
     RECT  35.7 84.7 49.98 124.18 ;
     RECT  35.7 138.46 49.98 139.3 ;
     RECT  47.74 18.62 50.26 71.54 ;
     RECT  50.26 18.06 50.54 71.54 ;
     RECT  50.54 18.06 51.27 72.1 ;
     RECT  49.98 84.7 51.27 139.3 ;
     RECT  45.5 154.14 51.27 232.26 ;
     RECT  51.27 18.06 51.66 341.18 ;
     RECT  51.66 14.7 52.17 341.18 ;
     RECT  52.17 14.7 53.85 337.26 ;
     RECT  53.85 107.66 54.96 232.26 ;
     RECT  53.85 14.7 57.26 96.18 ;
     RECT  54.96 107.66 66.22 131.46 ;
     RECT  54.96 142.94 66.22 232.26 ;
     RECT  66.22 107.66 69.02 232.26 ;
     RECT  57.26 16.38 69.58 96.18 ;
     RECT  69.02 107.66 69.58 232.82 ;
     RECT  69.58 16.38 71.27 232.82 ;
     RECT  71.27 16.38 72.17 341.18 ;
     RECT  72.17 16.38 72.95 337.26 ;
     RECT  72.95 15.54 73.85 337.26 ;
     RECT  73.85 28.14 74.9 230.58 ;
     RECT  74.9 33.74 76.58 230.58 ;
     RECT  76.58 34.86 77.14 81.62 ;
     RECT  77.14 37.1 78.26 81.62 ;
     RECT  76.58 158.06 79.28 230.58 ;
     RECT  78.26 37.66 91.27 81.62 ;
     RECT  76.58 95.9 91.27 143.78 ;
     RECT  79.28 158.06 91.27 169.54 ;
     RECT  79.28 181.58 91.27 230.58 ;
     RECT  91.27 19.46 92.17 341.18 ;
     RECT  92.17 19.46 92.95 337.26 ;
     RECT  92.95 15.54 93.85 337.26 ;
     RECT  93.85 99.82 95.06 109.62 ;
     RECT  93.85 121.1 95.06 164.5 ;
     RECT  93.85 63.98 95.62 80.5 ;
     RECT  95.06 103.74 96.18 109.62 ;
     RECT  106.54 35.98 107.1 36.26 ;
     RECT  96.18 104.86 107.66 109.62 ;
     RECT  95.06 123.9 107.66 164.5 ;
     RECT  107.66 104.86 108.03 164.5 ;
     RECT  108.03 100.38 108.78 164.5 ;
     RECT  107.1 35.98 109.71 46.34 ;
     RECT  95.62 63.98 109.71 76.58 ;
     RECT  108.78 88.06 110.46 164.5 ;
     RECT  93.85 177.66 110.46 230.58 ;
     RECT  109.71 35.98 111.27 76.58 ;
     RECT  110.46 88.06 111.27 230.58 ;
     RECT  111.27 19.46 112.17 341.18 ;
     RECT  112.17 19.46 112.95 337.26 ;
     RECT  112.95 15.54 113.85 337.26 ;
     RECT  113.85 60.62 114.66 186.9 ;
     RECT  113.85 205.1 115.22 205.38 ;
     RECT  113.85 35.98 116.34 49.14 ;
     RECT  116.34 36.54 116.9 49.14 ;
     RECT  114.66 60.62 116.9 134.26 ;
     RECT  114.66 145.74 116.9 186.9 ;
     RECT  116.9 83.02 117.46 134.26 ;
     RECT  117.46 111.02 128.94 134.26 ;
     RECT  116.9 145.74 128.94 166.74 ;
     RECT  117.46 83.02 129.5 96.18 ;
     RECT  128.94 111.02 129.5 166.74 ;
     RECT  116.9 60.62 130.62 69.86 ;
     RECT  129.5 83.02 130.62 166.74 ;
     RECT  116.9 37.1 131.27 49.14 ;
     RECT  130.62 60.62 131.27 166.74 ;
     RECT  116.9 178.22 131.27 182.42 ;
     RECT  131.27 19.46 132.17 341.18 ;
     RECT  132.17 19.46 132.95 337.26 ;
     RECT  132.95 15.54 133.85 337.26 ;
     RECT  133.85 60.62 135.1 167.3 ;
     RECT  135.1 60.62 135.38 131.46 ;
     RECT  135.38 60.62 138.74 109.62 ;
     RECT  133.85 40.46 146.11 46.34 ;
     RECT  138.74 60.62 146.11 109.06 ;
     RECT  135.38 123.34 148.54 131.46 ;
     RECT  135.1 142.94 148.54 167.3 ;
     RECT  133.85 18.62 151.27 18.9 ;
     RECT  146.11 40.46 151.27 109.06 ;
     RECT  148.54 123.34 151.27 167.3 ;
     RECT  151.27 18.62 152.17 341.18 ;
     RECT  152.17 18.62 152.95 337.26 ;
     RECT  152.95 15.54 153.85 337.26 ;
     RECT  153.85 41.58 154.98 119.14 ;
     RECT  153.85 142.94 156.38 167.3 ;
     RECT  156.38 142.94 157.22 166.18 ;
     RECT  154.98 41.58 157.78 68.74 ;
     RECT  157.22 142.94 159.46 162.82 ;
     RECT  154.98 80.78 166.46 119.14 ;
     RECT  153.85 130.62 166.46 130.9 ;
     RECT  159.46 142.94 166.46 147.14 ;
     RECT  159.46 158.62 168.7 162.82 ;
     RECT  157.78 41.58 170.19 64.82 ;
     RECT  166.46 80.22 170.19 119.14 ;
     RECT  168.7 158.62 170.38 163.94 ;
     RECT  170.19 41.58 170.94 119.14 ;
     RECT  166.46 130.62 170.94 147.14 ;
     RECT  153.85 24.78 171.27 25.06 ;
     RECT  170.94 41.58 171.27 147.14 ;
     RECT  170.38 158.62 171.27 165.62 ;
     RECT  171.27 19.46 172.17 341.18 ;
     RECT  172.17 19.46 172.95 337.26 ;
     RECT  172.95 15.54 173.85 337.26 ;
     RECT  173.85 49.42 174.48 104.02 ;
     RECT  174.48 49.42 174.58 100.66 ;
     RECT  173.85 117.74 175.04 143.22 ;
     RECT  174.58 49.42 175.7 72.66 ;
     RECT  173.85 158.62 177.84 165.62 ;
     RECT  175.7 49.42 187.18 70.42 ;
     RECT  175.04 117.74 190.54 127.54 ;
     RECT  175.04 139.02 190.54 143.22 ;
     RECT  177.84 158.62 190.54 162.82 ;
     RECT  187.18 49.42 191.27 72.66 ;
     RECT  174.58 84.14 191.27 100.66 ;
     RECT  190.54 117.74 191.27 143.22 ;
     RECT  190.54 158.62 191.27 164.5 ;
     RECT  189.42 303.66 191.27 303.94 ;
     RECT  191.27 19.46 192.17 341.18 ;
     RECT  192.17 19.46 192.95 337.26 ;
     RECT  192.95 15.54 193.85 337.26 ;
     RECT  193.85 244.86 205.1 265.3 ;
     RECT  193.85 280.14 206.78 334.18 ;
     RECT  205.1 238.14 206.875 265.3 ;
     RECT  193.85 84.14 207.34 151.06 ;
     RECT  193.85 162.54 207.34 166.74 ;
     RECT  206.875 235.34 208.46 265.3 ;
     RECT  207.34 84.14 209.86 166.74 ;
     RECT  208.46 235.34 210.14 267.54 ;
     RECT  206.78 280.14 210.14 335.86 ;
     RECT  210.14 235.34 210.7 335.86 ;
     RECT  193.85 49.98 211.27 72.66 ;
     RECT  209.86 84.14 211.27 169.54 ;
     RECT  210.7 230.3 211.27 335.86 ;
     RECT  211.27 19.46 212.17 341.18 ;
     RECT  212.17 19.46 212.95 338.1 ;
     RECT  212.95 15.54 213.85 338.1 ;
     RECT  213.85 53.34 217.7 170.66 ;
     RECT  217.7 53.34 218.82 53.62 ;
     RECT  213.85 216.3 218.82 338.1 ;
     RECT  217.7 67.9 227.5 170.66 ;
     RECT  218.82 216.3 230.3 267.54 ;
     RECT  218.82 281.26 230.3 338.1 ;
     RECT  227.5 67.9 231.27 175.7 ;
     RECT  230.3 216.3 231.27 338.1 ;
     RECT  231.27 19.46 232.17 341.18 ;
     RECT  232.17 19.46 232.95 338.1 ;
     RECT  232.95 15.54 233.85 338.1 ;
     RECT  233.85 214.06 234.5 338.1 ;
     RECT  234.5 260.54 237.86 338.1 ;
     RECT  233.85 67.9 238.42 202.02 ;
     RECT  238.42 141.82 248.22 202.02 ;
     RECT  234.5 214.06 248.22 248.5 ;
     RECT  248.22 141.82 249.06 248.5 ;
     RECT  249.06 141.82 249.34 249.06 ;
     RECT  237.86 260.54 249.34 307.3 ;
     RECT  238.42 67.9 249.9 124.74 ;
     RECT  249.9 65.66 251.27 124.74 ;
     RECT  249.34 141.82 251.27 307.3 ;
     RECT  237.86 319.34 251.27 338.1 ;
     RECT  251.27 19.46 252.17 341.18 ;
     RECT  252.17 19.46 252.95 337.26 ;
     RECT  252.95 15.54 253.85 337.26 ;
     RECT  253.85 72.38 254.66 264.18 ;
     RECT  253.85 275.66 254.66 307.3 ;
     RECT  257.74 358.54 260.26 358.82 ;
     RECT  254.66 275.66 267.07 303.38 ;
     RECT  267.07 275.66 267.54 307.86 ;
     RECT  253.85 322.14 267.54 335.86 ;
     RECT  267.54 275.66 267.82 335.86 ;
     RECT  254.66 72.38 271.27 147.7 ;
     RECT  254.66 159.74 271.27 264.18 ;
     RECT  267.82 275.66 271.27 340.34 ;
     RECT  271.27 19.46 272.17 341.18 ;
     RECT  272.17 19.46 272.95 337.26 ;
     RECT  272.95 15.54 273.85 337.26 ;
     RECT  273.85 72.38 274.26 310.66 ;
     RECT  274.26 76.3 274.82 310.66 ;
     RECT  274.82 127.26 277.62 310.66 ;
     RECT  277.62 127.26 278.835 143.22 ;
     RECT  277.62 154.7 279.86 310.66 ;
     RECT  279.86 288.54 285.18 310.66 ;
     RECT  285.18 288.54 290.03 311.78 ;
     RECT  273.85 323.26 290.03 331.38 ;
     RECT  274.82 76.3 291.27 115.78 ;
     RECT  278.835 127.26 291.27 139.3 ;
     RECT  279.86 154.7 291.27 276.5 ;
     RECT  290.03 288.54 291.27 331.38 ;
     RECT  291.27 19.46 292.17 341.18 ;
     RECT  292.17 19.46 292.95 337.26 ;
     RECT  292.95 15.54 293.85 337.26 ;
     RECT  293.85 237.02 293.86 241.78 ;
     RECT  293.85 139.02 296.1 190.26 ;
     RECT  293.85 256.62 296.1 335.3 ;
     RECT  296.1 260.26 297.78 335.3 ;
     RECT  293.86 240.94 298.34 241.78 ;
     RECT  298.34 241.5 299.46 241.78 ;
     RECT  296.1 139.02 307.02 151.62 ;
     RECT  293.85 76.3 310.94 124.18 ;
     RECT  307.02 136.22 310.94 151.62 ;
     RECT  296.1 169.26 310.94 190.26 ;
     RECT  310.94 76.3 311.27 151.62 ;
     RECT  310.94 165.9 311.27 190.26 ;
     RECT  293.85 201.74 311.27 222.74 ;
     RECT  297.78 261.1 311.27 335.3 ;
     RECT  311.27 19.46 312.17 341.18 ;
     RECT  312.17 19.46 312.95 337.26 ;
     RECT  312.95 15.54 313.85 337.26 ;
     RECT  313.85 286.86 314.58 292.18 ;
     RECT  313.85 88.62 315.14 224.42 ;
     RECT  314.58 286.86 315.14 287.7 ;
     RECT  313.85 304.78 315.14 319.62 ;
     RECT  315.14 88.62 316.12 189.7 ;
     RECT  316.12 88.62 317.38 189.14 ;
     RECT  315.14 201.18 329.14 224.42 ;
     RECT  317.38 88.62 331.27 183.54 ;
     RECT  329.14 201.18 331.27 226.66 ;
     RECT  313.85 272.3 331.27 272.58 ;
     RECT  315.14 287.42 331.27 287.7 ;
     RECT  315.14 304.78 331.27 316.82 ;
     RECT  331.27 19.46 332.17 341.18 ;
     RECT  332.17 19.46 332.95 337.26 ;
     RECT  332.95 15.54 333.85 337.26 ;
     RECT  333.85 169.26 339.22 181.3 ;
     RECT  333.85 96.46 341.09 109.06 ;
     RECT  333.85 125.58 341.09 125.86 ;
     RECT  333.85 141.26 341.09 150.5 ;
     RECT  339.22 169.26 341.09 180.74 ;
     RECT  333.85 225.26 341.09 226.66 ;
     RECT  333.85 287.98 341.09 288.26 ;
    LAYER Metal4 ;
     RECT  11.16 15.38 13.96 25.34 ;
     RECT  9.66 25.34 13.96 27.86 ;
     RECT  111.16 15.38 113.96 41.02 ;
     RECT  151.16 15.38 153.96 42.7 ;
     RECT  109.9 41.02 113.96 43.82 ;
     RECT  146.3 42.7 153.96 49.7 ;
     RECT  171.16 15.38 173.96 53.34 ;
     RECT  151.16 49.7 153.96 56.7 ;
     RECT  109.9 43.82 115.78 56.98 ;
     RECT  151.16 56.7 154.98 60.9 ;
     RECT  111.16 56.98 115.78 64.26 ;
     RECT  251.16 15.38 253.96 72.38 ;
     RECT  170.38 53.34 173.96 72.66 ;
     RECT  71.16 15.38 73.96 76.86 ;
     RECT  67.34 76.86 73.96 82.18 ;
     RECT  291.16 15.38 293.96 84.14 ;
     RECT  251.16 72.38 259.14 86.94 ;
     RECT  250.46 86.94 259.14 91.14 ;
     RECT  287.42 84.14 293.96 91.7 ;
     RECT  251.16 91.14 259.14 92.26 ;
     RECT  11.16 27.86 13.96 99.82 ;
     RECT  11.16 99.82 14.98 115.78 ;
     RECT  111.16 64.26 115.22 127.26 ;
     RECT  171.16 72.66 173.96 142.38 ;
     RECT  168.7 142.38 173.96 144.9 ;
     RECT  109.9 127.26 115.22 149.66 ;
     RECT  131.16 15.38 133.96 150.78 ;
     RECT  191.16 15.38 193.96 158.62 ;
     RECT  190.54 158.62 193.96 164.5 ;
     RECT  211.16 15.38 213.96 165.9 ;
     RECT  311.16 15.38 313.96 166.46 ;
     RECT  251.16 92.26 253.96 167.58 ;
     RECT  211.16 165.9 214.9 170.66 ;
     RECT  251.16 167.58 256.34 179.62 ;
     RECT  128.38 150.78 133.96 181.86 ;
     RECT  311.16 166.46 316.26 189.7 ;
     RECT  31.16 15.38 33.96 189.98 ;
     RECT  51.16 15.38 53.96 189.98 ;
     RECT  109.34 149.66 115.22 197.54 ;
     RECT  31.16 189.98 53.96 202.02 ;
     RECT  109.9 197.54 115.22 205.38 ;
     RECT  109.9 205.38 113.96 208.74 ;
     RECT  231.16 15.38 233.96 225.26 ;
     RECT  251.16 179.62 253.96 225.26 ;
     RECT  211.16 170.66 213.96 251.58 ;
     RECT  211.16 251.58 218.82 251.86 ;
     RECT  211.16 251.86 219.94 267.26 ;
     RECT  231.16 225.26 253.96 267.26 ;
     RECT  291.16 91.7 293.96 280.14 ;
     RECT  311.16 189.7 313.96 280.14 ;
     RECT  271.16 15.38 273.96 291.34 ;
     RECT  191.16 164.5 193.96 296.38 ;
     RECT  211.16 267.26 253.96 296.38 ;
     RECT  291.16 280.14 313.96 304.78 ;
     RECT  271.16 291.34 277.06 307.3 ;
     RECT  271.16 307.3 273.96 307.58 ;
     RECT  290.22 304.78 313.96 311.22 ;
     RECT  267.26 307.58 273.96 322.42 ;
     RECT  290.22 311.22 293.96 322.42 ;
     RECT  191.16 296.38 253.96 322.98 ;
     RECT  211.16 322.98 253.96 338.1 ;
     RECT  11.16 115.78 13.96 341.34 ;
     RECT  31.16 202.02 33.96 341.34 ;
     RECT  51.16 202.02 53.96 341.34 ;
     RECT  71.16 82.18 73.96 341.34 ;
     RECT  91.16 15.38 93.96 341.34 ;
     RECT  111.16 208.74 113.96 341.34 ;
     RECT  131.16 181.86 133.96 341.34 ;
     RECT  151.16 60.9 153.96 341.34 ;
     RECT  171.16 144.9 173.96 341.34 ;
     RECT  191.16 322.98 193.96 341.34 ;
     RECT  211.16 338.1 213.96 341.34 ;
     RECT  231.16 338.1 233.96 341.34 ;
     RECT  251.16 338.1 253.96 341.34 ;
     RECT  271.16 322.42 273.96 341.34 ;
     RECT  291.16 322.42 293.96 341.34 ;
     RECT  311.16 311.22 313.96 341.34 ;
     RECT  331.16 15.38 333.96 341.34 ;
    LAYER Metal5 ;
     RECT  6.72 20.23 334.32 341.13 ;
  END
END PLL_COUNTER_DCO_PHYS
END LIBRARY
